VERSION 5.8 ;
UNITS
   DATABASE MICRONS 2000 ;
END UNITS

VIA VIA12
   LAYER M1 ;
      RECT -0.10 -0.10 0.10 0.10 ;
   LAYER VIA1 ;
      RECT -0.05 -0.05 0.05 0.05 ;
   LAYER M2 ;
      RECT -0.12 -0.12 0.12 0.12 ;
END VIA12

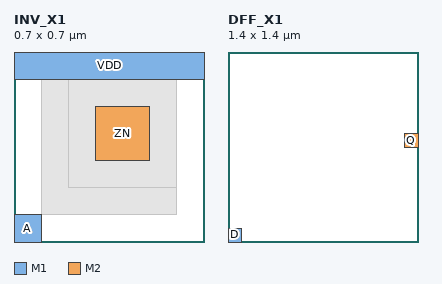
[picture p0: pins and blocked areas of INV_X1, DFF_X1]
MACRO INV_X1
   CLASS CORE ;
   ORIGIN 0 0 ;
   SIZE 0.7 BY 0.7 ;
   SITE site1 ;
   PIN A
      DIRECTION INPUT ;
      USE SIGNAL ;
      PORT
         LAYER M1 ;
            RECT 0.0 0.0 0.1 0.1 ;
      END
   END A
   PIN ZN
      DIRECTION OUTPUT ;
      USE SIGNAL ;
      PORT
         LAYER M2 ;
            RECT 0.3 0.3 0.5 0.5 ;
      END
   END ZN
   PIN VDD
      DIRECTION INOUT ;
      USE POWER ;
      PORT
         LAYER M1 ;
            RECT 0.0 0.6 0.7 0.7 ;
      END
   END VDD
   OBS
      LAYER M1 ;
         RECT 0.1 0.1 0.6 0.6 ;
      LAYER M2 ;
         RECT 0.2 0.2 0.6 0.6 ;
   END
END INV_X1

MACRO DFF_X1
   CLASS CORE ;
   SIZE 1.4 BY 1.4 ;
   PIN D
      DIRECTION INPUT ;
      USE SIGNAL ;
      PORT
         LAYER M1 ;
            RECT 0.0 0.0 0.1 0.1 ;
      END
   END D
   PIN Q
      DIRECTION OUTPUT ;
      USE SIGNAL ;
      PORT
         LAYER M2 ;
            RECT 1.3 0.7 1.4 0.8 ;
      END
   END Q
END DFF_X1

MACRO INV_X1
   CLASS BLOCK ;
   SIZE 9.9 BY 9.9 ;
END INV_X1

END LIBRARY
